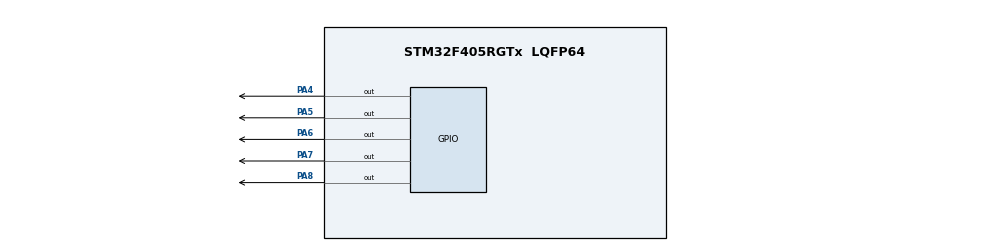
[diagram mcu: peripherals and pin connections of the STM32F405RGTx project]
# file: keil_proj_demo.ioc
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Mcu.Family=STM32F4
Mcu.Name=STM32F405RGTx
Mcu.Package=LQFP64
NVIC.PriorityGroup=NVIC_PRIORITYGROUP_4
PA4.Signal=GPIO_Output
PA5.Signal=GPIO_Output
PA6.Signal=GPIO_Output
PA7.Signal=GPIO_Output
PA8.Signal=GPIO_Output
ProjectManager.HeapSize=0x200
ProjectManager.StackSize=0x400
ProjectManager.TargetToolchain=MDK-ARM V5.32
RCC.48MHZClocksFreq_Value=84000000
RCC.AHBFreq_Value=168000000
RCC.APB1CLKDivider=RCC_HCLK_DIV4
RCC.APB1Freq_Value=42000000
RCC.APB1TimFreq_Value=84000000
RCC.APB2CLKDivider=RCC_HCLK_DIV2
RCC.APB2Freq_Value=84000000
RCC.APB2TimFreq_Value=168000000
RCC.CortexFreq_Value=168000000
RCC.HCLKFreq_Value=168000000
RCC.HSE_VALUE=25000000
RCC.HSI_VALUE=16000000
RCC.LSE_VALUE=32768
RCC.PLLM=8
RCC.PLLN=168
RCC.SYSCLKFreq_VALUE=168000000
RCC.SYSCLKSource=RCC_SYSCLKSOURCE_PLLCLK
RCC.VCOOutputFreq_Value=336000000
board=custom

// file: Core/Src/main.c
/* USER CODE BEGIN Header */
/**
  ******************************************************************************
  * @file           : main.c
  * @brief          : Main program body
  ******************************************************************************
  * @attention
  *
  * Copyright (c) 2026 STMicroelectronics.
  * All rights reserved.
  *
  * This software is licensed under terms that can be found in the LICENSE file
  * in the root directory of this software component.
  * If no LICENSE file comes with this software, it is provided AS-IS.
  *
  ******************************************************************************
  */
/* USER CODE END Header */
#include "main.h"
#include "gpio.h"

/* USER CODE BEGIN Includes */
/*
 * 为什么调用自己的文件时，要先把 .c 文件加进 Keil 工程？
 * 1. Keil 不会自动扫描文件夹里的源码，只有 .uvprojx 中列出的 .c 文件才会参与编译；
 * 2. 头文件 .h 只负责声明函数，函数的真正实现还在 .c 文件里；
 * 3. 如果只 #include 头文件但没有把 .c 加进工程，编译可能通过，
 *    但链接时会报 Undefined symbol 之类的错误，因为找不到函数实现；
 * 4. 需要先在keil文件夹中创建Group,在Group内添加已存在的c文件;
 * 5. 还需要在 Options for Target -> C/C++ -> Include Paths 中加上 .h 所在目录，
 *    否则编译器连头文件都找不到。
 * 本工程已经把 hardware/src/buzzer.c 和 led.c 加进 Keil 工程的 hardware 分组，
 * 并把 hardware/inc 加进 Include Paths，所以这里可以直接包含并使用。
 */
#include "buzzer.h"   /* 蜂鸣器驱动的函数声明 */
#include "led.h"      /* LED 驱动的函数声明 */

// 在这里替换成#include user_beep.h

/* USER CODE END Includes */

/* USER CODE BEGIN PD */
/* #define 是宏定义：编译前会把名字替换成后面的内容 */
#define LED_COUNT   4U    /* 板载 LED 数量，U 表示 unsigned 无符号数 */
#define BLINK_TIMES 5U    /* 每颗 LED 闪烁次数 */
#define DELAY_MS    250U  /* LED 亮/灭持续时间，单位毫秒 */
#define BEEP_MS     120U  /* 蜂鸣器响一声的时长 */
/* USER CODE END PD */

void SystemClock_Config(void);
static void MPU_Config(void);
/* USER CODE BEGIN PFP */
/* 函数声明（原型）：告诉编译器函数名、参数和返回值，定义在下方 USER CODE 4 */
void blink_led(uint8_t led_num, uint16_t times, uint32_t delay_ms);
void beep(uint32_t beep_ms);
/* USER CODE END PFP */

/* USER CODE BEGIN 0 */
__weak void user_beep(){}
/* USER CODE END 0 */

int main(void)
{

  /* USER CODE BEGIN 1 */
  /* 局部变量：只能在 main 函数内使用 */
  uint8_t  current_led = 1U;              /* 当前要操作的 LED 编号 */
  uint16_t blink_times = BLINK_TIMES;/* 每颗 LED 闪烁次数 */
  uint32_t delay_ms    = DELAY_MS;   /* 亮/灭延时 */
  const uint8_t led_count = LED_COUNT; /* const 表示该变量不允许修改 */
  /* USER CODE END 1 */

  /* MPU Configuration--------------------------------------------------------*/
  MPU_Config();

  /* MCU Configuration--------------------------------------------------------*/

  /* Reset of all peripherals, Initializes the Flash interface and the Systick. */
  HAL_Init();

  /* Configure the system clock */
  SystemClock_Config();

  /* Initialize all configured peripherals */
  MX_GPIO_Init();
  /* USER CODE BEGIN 2 */
  buzzer_init(); /* 让蜂鸣器引脚先处于关闭状态 */
  user_beep();
  /* USER CODE END 2 */

  /* Infinite loop */
  while (1)
  {

    /* USER CODE BEGIN 3 */
    current_led = 1U; /* 练习点：改成 2U，观察从哪颗 LED 开始 */

    /* while 循环：条件成立就反复执行 {} 里的代码 */
    while (current_led <= led_count)
    {
      blink_led(current_led, blink_times, delay_ms);
      current_led++; /* 等价于 current_led = current_led + 1 */
    }

    beep(BEEP_MS);

    /* if / else 判断：让延时每次变快一点，到 100 后重新回到初始值 */
    if (delay_ms > 100U)
    {
      delay_ms -= 20U; /* 练习点：改成 += 20U 看速度变化方向 */
    }
    else
    {
      delay_ms = DELAY_MS;
    }
  }
  /* USER CODE END 3 */
}

void SystemClock_Config(void)
{
  RCC_OscInitTypeDef RCC_OscInitStruct = {0};
  RCC_ClkInitTypeDef RCC_ClkInitStruct = {0};

  /** Supply configuration update enable
  */
  HAL_PWREx_ConfigSupply(PWR_LDO_SUPPLY);

  /** Configure the main internal regulator output voltage
  */
  __HAL_PWR_VOLTAGESCALING_CONFIG(PWR_REGULATOR_VOLTAGE_SCALE0);

  while(!__HAL_PWR_GET_FLAG(PWR_FLAG_VOSRDY)) {}

  /** Initializes the RCC Oscillators according to the specified parameters
  * in the RCC_OscInitTypeDef structure.
  */
  RCC_OscInitStruct.OscillatorType = RCC_OSCILLATORTYPE_HSI;
  RCC_OscInitStruct.HSIState = RCC_HSI_DIV1;
  RCC_OscInitStruct.HSICalibrationValue = 64;
  RCC_OscInitStruct.PLL.PLLState = RCC_PLL_ON;
  RCC_OscInitStruct.PLL.PLLSource = RCC_PLLSOURCE_HSI;
  RCC_OscInitStruct.PLL.PLLM = 4;
  RCC_OscInitStruct.PLL.PLLN = 34;
  RCC_OscInitStruct.PLL.PLLP = 1;
  RCC_OscInitStruct.PLL.PLLQ = 2;
  RCC_OscInitStruct.PLL.PLLR = 2;
  RCC_OscInitStruct.PLL.PLLRGE = RCC_PLL1VCIRANGE_3;
  RCC_OscInitStruct.PLL.PLLVCOSEL = RCC_PLL1VCOWIDE;
  RCC_OscInitStruct.PLL.PLLFRACN = 3072;
  if (HAL_RCC_OscConfig(&RCC_OscInitStruct) != HAL_OK)
  {
    Error_Handler();
  }

  /** Initializes the CPU, AHB and APB buses clocks
  */
  RCC_ClkInitStruct.ClockType = RCC_CLOCKTYPE_HCLK|RCC_CLOCKTYPE_SYSCLK
                              |RCC_CLOCKTYPE_PCLK1|RCC_CLOCKTYPE_PCLK2
                              |RCC_CLOCKTYPE_D3PCLK1|RCC_CLOCKTYPE_D1PCLK1;
  RCC_ClkInitStruct.SYSCLKSource = RCC_SYSCLKSOURCE_PLLCLK;
  RCC_ClkInitStruct.SYSCLKDivider = RCC_SYSCLK_DIV1;
  RCC_ClkInitStruct.AHBCLKDivider = RCC_HCLK_DIV2;
  RCC_ClkInitStruct.APB3CLKDivider = RCC_APB3_DIV2;
  RCC_ClkInitStruct.APB1CLKDivider = RCC_APB1_DIV2;
  RCC_ClkInitStruct.APB2CLKDivider = RCC_APB2_DIV2;
  RCC_ClkInitStruct.APB4CLKDivider = RCC_APB4_DIV2;

  if (HAL_RCC_ClockConfig(&RCC_ClkInitStruct, FLASH_LATENCY_3) != HAL_OK)
  {
    Error_Handler();
  }
}

/* USER CODE BEGIN 4 */
/* 函数定义：这里才是函数的具体实现 */
void blink_led(uint8_t led_num, uint16_t times, uint32_t delay_ms)
{
  uint16_t i = 0U; /* 循环计数变量 */

  /* if 判断：LED 编号只允许 1~4 */
  if (led_num > LED_COUNT)
  {
    return; /* return 直接结束当前函数 */
  }

  /* for 循环：初始化; 判断条件; 每次循环后执行 */
  for (i = 0U; i < times; i++)
  {
    led_on(led_num);          /* 点亮指定 LED */
    HAL_Delay(delay_ms);      /* 延时一段时间 */
    led_off(led_num);         /* 熄灭指定 LED */
    HAL_Delay(delay_ms);
  }
}

void beep(uint32_t beep_ms)
{
  buzzer_on();          /* 打开蜂鸣器 */
  HAL_Delay(beep_ms);   /* 保持响一段时间 */
  buzzer_off();         /* 关闭蜂鸣器 */
}
/* USER CODE END 4 */

 /* MPU Configuration */

void MPU_Config(void)
{
  MPU_Region_InitTypeDef MPU_InitStruct = {0};

  /* Disables the MPU */
  HAL_MPU_Disable();

  /** Initializes and configures the Region and the memory to be protected
  */
  MPU_InitStruct.Enable = MPU_REGION_ENABLE;
  MPU_InitStruct.Number = MPU_REGION_NUMBER0;
  MPU_InitStruct.BaseAddress = 0x0;
  MPU_InitStruct.Size = MPU_REGION_SIZE_4GB;
  MPU_InitStruct.SubRegionDisable = 0x87;
  MPU_InitStruct.TypeExtField = MPU_TEX_LEVEL0;
  MPU_InitStruct.AccessPermission = MPU_REGION_NO_ACCESS;
  MPU_InitStruct.DisableExec = MPU_INSTRUCTION_ACCESS_DISABLE;
  MPU_InitStruct.IsShareable = MPU_ACCESS_SHAREABLE;
  MPU_InitStruct.IsCacheable = MPU_ACCESS_NOT_CACHEABLE;
  MPU_InitStruct.IsBufferable = MPU_ACCESS_NOT_BUFFERABLE;

  HAL_MPU_ConfigRegion(&MPU_InitStruct);
  /* Enables the MPU */
  HAL_MPU_Enable(MPU_PRIVILEGED_DEFAULT);

}

void Error_Handler(void)
{
  __disable_irq();
  while (1)
  {
  }
}
